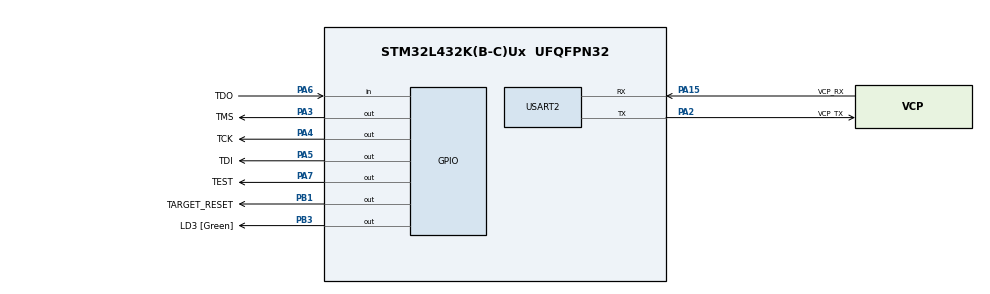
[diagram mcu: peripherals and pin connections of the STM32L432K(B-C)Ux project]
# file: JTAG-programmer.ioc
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Mcu.Family=STM32L4
Mcu.Name=STM32L432K(B-C)Ux
Mcu.Package=UFQFPN32
NVIC.PriorityGroup=NVIC_PRIORITYGROUP_4
PA0.GPIO_Label=MCO [High speed clock in]
PA0.Mode=HSE-External-Clock-Source-for-LittleOrca
PA0.Signal=RCC_CK_IN
PA13\ (JTMS-SWDIO).GPIO_Label=SWDIO
PA13\ (JTMS-SWDIO).Mode=Serial_Wire
PA13\ (JTMS-SWDIO).Signal=SYS_JTMS-SWDIO
PA14\ (JTCK-SWCLK).GPIO_Label=SWCLK
PA14\ (JTCK-SWCLK).Mode=Serial_Wire
PA14\ (JTCK-SWCLK).Signal=SYS_JTCK-SWCLK
PA15\ (JTDI).GPIO_Label=VCP_RX
PA15\ (JTDI).Mode=Asynchronous
PA15\ (JTDI).Signal=USART2_RX
PA2.GPIO_Label=VCP_TX
PA2.Mode=Asynchronous
PA2.Signal=USART2_TX
PA3.GPIO_Label=TMS
PA3.GPIO_Speed=GPIO_SPEED_FREQ_VERY_HIGH
PA3.Signal=GPIO_Output
PA4.GPIO_Label=TCK
PA4.GPIO_Speed=GPIO_SPEED_FREQ_VERY_HIGH
PA4.Signal=GPIO_Output
PA5.GPIO_Label=TDI
PA5.GPIO_Speed=GPIO_SPEED_FREQ_VERY_HIGH
PA5.Signal=GPIO_Output
PA6.GPIO_Label=TDO
PA6.Signal=GPIO_Input
PA7.GPIO_Label=TEST
PA7.GPIO_Speed=GPIO_SPEED_FREQ_VERY_HIGH
PA7.Signal=GPIO_Output
PB1.GPIO_Label=TARGET_RESET
PB1.GPIO_Speed=GPIO_SPEED_FREQ_VERY_HIGH
PB1.Signal=GPIO_Output
PB3\ (JTDO-TRACESWO).GPIO_Label=LD3 [Green]
PB3\ (JTDO-TRACESWO).Signal=GPIO_Output
PC14-OSC32_IN\ (PC14).Mode=LSE-External-Oscillator
PC14-OSC32_IN\ (PC14).Signal=RCC_OSC32_IN
PC15-OSC32_OUT\ (PC15).Mode=LSE-External-Oscillator
PC15-OSC32_OUT\ (PC15).Signal=RCC_OSC32_OUT
ProjectManager.HeapSize=0x200
ProjectManager.StackSize=0x400
ProjectManager.TargetToolchain=STM32CubeIDE
RCC.AHBFreq_Value=16000000
RCC.APB1Freq_Value=16000000
RCC.APB1TimFreq_Value=16000000
RCC.APB2Freq_Value=16000000
RCC.APB2TimFreq_Value=16000000
RCC.CortexFreq_Value=16000000
RCC.HCLKFreq_Value=16000000
RCC.HSE_VALUE=8000000
RCC.HSI16_VALUE=16000000
RCC.HSI48_VALUE=48000000
RCC.HSI_VALUE=16000000
RCC.MSI_VALUE=4000000
RCC.PLLMUL=RCC_PLLMUL_4
RCC.PLLN=16
RCC.SYSCLKFreq_VALUE=16000000
RCC.SYSCLKSource=RCC_SYSCLKSOURCE_HSI
RCC.VCOOutputFreq_Value=64000000
USART2.VirtualMode-Asynchronous=VM_ASYNC
board=NUCLEO-L432KC

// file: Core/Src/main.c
/* USER CODE BEGIN Header */
/**
 ******************************************************************************
 * @file           : main.c
 * @brief          : Main program body
 ******************************************************************************
 * @attention
 *
 * Copyright (c) 2023 STMicroelectronics.
 * All rights reserved.
 *
 * This software is licensed under terms that can be found in the LICENSE file
 * in the root directory of this software component.
 * If no LICENSE file comes with this software, it is provided AS-IS.
 *
 ******************************************************************************
 */

/* USER CODE END Header */
#include "main.h"

/* USER CODE BEGIN Includes */
#include "stdio.h" // for printf
#include "JTAGfunc430.h"
#include "LowLevelFunc430.h"
#include "Devices430.h"
#include <memory.h> // for memset
#include <string.h> // for strncmp

//mine
#include "jtag_programmer.h"
#include "stdlib.h" // for malloc
/* USER CODE END Includes */

UART_HandleTypeDef huart2;

/* USER CODE BEGIN PV */
#ifdef __GNUC__
#define PUTCHAR_PROTOTYPE int __io_putchar(int ch)
#define GETCHAR_PROTOTYPE int __io_getchar(void)
#else
#define PUTCHAR_PROTOTYPE int fputc(int ch, FILE *f)
#define GETCHAR_PROTOTYPE int fgetc(FILE *f)
#endif

PUTCHAR_PROTOTYPE
{
  HAL_UART_Transmit(&huart2, (uint8_t *)&ch, 1, HAL_MAX_DELAY);
  return ch;
}

GETCHAR_PROTOTYPE
{
  uint8_t ch = 0;

  /* Clear the Overrun flag just before receiving the first character */
  __HAL_UART_CLEAR_OREFLAG(&huart2);

  /* Wait for reception of a character on the USART RX line and echo this
   * character on console */
  HAL_UART_Receive(&huart2, (uint8_t *)&ch, 1, HAL_MAX_DELAY);
  HAL_UART_Transmit(&huart2, (uint8_t *)&ch, 1, HAL_MAX_DELAY);
  return ch;
}
/* USER CODE END PV */

void SystemClock_Config(void);
static void MX_GPIO_Init(void);
static void MX_USART2_UART_Init(void);
/* USER CODE BEGIN PFP */
static void GPIO_DeInit(void);
static void GPIO_ReInit(void);
/* USER CODE END PFP */

/* USER CODE BEGIN 0 */

// return minimum of a and b. if equal, return a.
int min(int a, int b) {
	return (b < a) ? b : a;
}

/* USER CODE END 0 */

int main(void)
{

  /* MCU Configuration--------------------------------------------------------*/

  /* Reset of all peripherals, Initializes the Flash interface and the Systick. */
  HAL_Init();

  /* Configure the system clock */
  SystemClock_Config();

  /* Initialize all configured peripherals */
  MX_GPIO_Init();
  MX_USART2_UART_Init();

  /* Infinite loop */
  /* USER CODE BEGIN WHILE */
  while (1) {
	  char buf[16] = {0};
	  uint16_t buflen = 0;

	  HAL_StatusTypeDef ret = HAL_UARTEx_ReceiveToIdle(&huart2, (uint8_t*)&buf[0], 16, &buflen, TIMEOUT);
	  if(ret == HAL_OK) {
		  if(strncmp(buf, "Wakeup!", min(buflen, 7)) == 0) {
			  __HAL_UART_FLUSH_DRREGISTER(&huart2);
			  GPIO_ReInit();
			  program_sequence();
			  GPIO_DeInit();
		  }
	  } else {
		  printf("-vret is %d and received %d bytes : %s\n", ret, buflen, buf);
	  }

	  HAL_GPIO_TogglePin(LD3_GPIO_Port, LD3_Pin);
    /* USER CODE END WHILE */

	}
}

void SystemClock_Config(void)
{
  RCC_OscInitTypeDef RCC_OscInitStruct = {0};
  RCC_ClkInitTypeDef RCC_ClkInitStruct = {0};

  /** Configure the main internal regulator output voltage
  */
  if (HAL_PWREx_ControlVoltageScaling(PWR_REGULATOR_VOLTAGE_SCALE1) != HAL_OK)
  {
    Error_Handler();
  }

  /** Initializes the RCC Oscillators according to the specified parameters
  * in the RCC_OscInitTypeDef structure.
  */
  RCC_OscInitStruct.OscillatorType = RCC_OSCILLATORTYPE_HSI;
  RCC_OscInitStruct.HSIState = RCC_HSI_ON;
  RCC_OscInitStruct.HSICalibrationValue = RCC_HSICALIBRATION_DEFAULT;
  RCC_OscInitStruct.PLL.PLLState = RCC_PLL_NONE;
  if (HAL_RCC_OscConfig(&RCC_OscInitStruct) != HAL_OK)
  {
    Error_Handler();
  }

  /** Initializes the CPU, AHB and APB buses clocks
  */
  RCC_ClkInitStruct.ClockType = RCC_CLOCKTYPE_HCLK|RCC_CLOCKTYPE_SYSCLK
                              |RCC_CLOCKTYPE_PCLK1|RCC_CLOCKTYPE_PCLK2;
  RCC_ClkInitStruct.SYSCLKSource = RCC_SYSCLKSOURCE_HSI;
  RCC_ClkInitStruct.AHBCLKDivider = RCC_SYSCLK_DIV2;
  RCC_ClkInitStruct.APB1CLKDivider = RCC_HCLK_DIV1;
  RCC_ClkInitStruct.APB2CLKDivider = RCC_HCLK_DIV1;

  if (HAL_RCC_ClockConfig(&RCC_ClkInitStruct, FLASH_LATENCY_0) != HAL_OK)
  {
    Error_Handler();
  }
}

static void MX_USART2_UART_Init(void)
{

  huart2.Instance = USART2;
  huart2.Init.BaudRate = 115200;
  huart2.Init.WordLength = UART_WORDLENGTH_8B;
  huart2.Init.StopBits = UART_STOPBITS_1;
  huart2.Init.Parity = UART_PARITY_NONE;
  huart2.Init.Mode = UART_MODE_TX_RX;
  huart2.Init.HwFlowCtl = UART_HWCONTROL_NONE;
  huart2.Init.OverSampling = UART_OVERSAMPLING_16;
  huart2.Init.OneBitSampling = UART_ONE_BIT_SAMPLE_DISABLE;
  huart2.AdvancedInit.AdvFeatureInit = UART_ADVFEATURE_RXOVERRUNDISABLE_INIT;
  huart2.AdvancedInit.OverrunDisable = UART_ADVFEATURE_OVERRUN_DISABLE;
  if (HAL_UART_Init(&huart2) != HAL_OK)
  {
    Error_Handler();
  }

}

static void MX_GPIO_Init(void)
{
  LL_GPIO_InitTypeDef GPIO_InitStruct = {0};

  /* GPIO Ports Clock Enable */
  LL_AHB2_GRP1_EnableClock(LL_AHB2_GRP1_PERIPH_GPIOC);
  LL_AHB2_GRP1_EnableClock(LL_AHB2_GRP1_PERIPH_GPIOA);
  LL_AHB2_GRP1_EnableClock(LL_AHB2_GRP1_PERIPH_GPIOB);
  LL_AHB2_GRP1_EnableClock(LL_AHB2_GRP1_PERIPH_GPIOH);

  /**/
  LL_GPIO_ResetOutputPin(GPIOA, TARGET_RESET_Pin|TMS_Pin|TCK_Pin|TDI_Pin
                          |TEST_Pin);

  /**/
  LL_GPIO_ResetOutputPin(LD3_GPIO_Port, LD3_Pin);

  /**/
  GPIO_InitStruct.Pin = TARGET_RESET_Pin|TMS_Pin|TCK_Pin|TDI_Pin
                          |TEST_Pin;
  GPIO_InitStruct.Mode = LL_GPIO_MODE_OUTPUT;
  GPIO_InitStruct.Speed = LL_GPIO_SPEED_FREQ_VERY_HIGH;
  GPIO_InitStruct.OutputType = LL_GPIO_OUTPUT_PUSHPULL;
  GPIO_InitStruct.Pull = LL_GPIO_PULL_NO;
  LL_GPIO_Init(GPIOA, &GPIO_InitStruct);

  /**/
  GPIO_InitStruct.Pin = TDO_Pin;
  GPIO_InitStruct.Mode = LL_GPIO_MODE_INPUT;
  GPIO_InitStruct.Pull = LL_GPIO_PULL_NO;
  LL_GPIO_Init(TDO_GPIO_Port, &GPIO_InitStruct);

  /**/
  GPIO_InitStruct.Pin = LL_GPIO_PIN_0|LL_GPIO_PIN_1|LL_GPIO_PIN_4|LL_GPIO_PIN_5
                          |LL_GPIO_PIN_6|LL_GPIO_PIN_7;
  GPIO_InitStruct.Mode = LL_GPIO_MODE_ANALOG;
  GPIO_InitStruct.Pull = LL_GPIO_PULL_NO;
  LL_GPIO_Init(GPIOB, &GPIO_InitStruct);

  /**/
  GPIO_InitStruct.Pin = LL_GPIO_PIN_8|LL_GPIO_PIN_9|LL_GPIO_PIN_10|LL_GPIO_PIN_11
                          |LL_GPIO_PIN_12;
  GPIO_InitStruct.Mode = LL_GPIO_MODE_ANALOG;
  GPIO_InitStruct.Pull = LL_GPIO_PULL_NO;
  LL_GPIO_Init(GPIOA, &GPIO_InitStruct);

  /**/
  GPIO_InitStruct.Pin = LD3_Pin;
  GPIO_InitStruct.Mode = LL_GPIO_MODE_OUTPUT;
  GPIO_InitStruct.Speed = LL_GPIO_SPEED_FREQ_LOW;
  GPIO_InitStruct.OutputType = LL_GPIO_OUTPUT_PUSHPULL;
  GPIO_InitStruct.Pull = LL_GPIO_PULL_NO;
  LL_GPIO_Init(LD3_GPIO_Port, &GPIO_InitStruct);

  /**/
  GPIO_InitStruct.Pin = LL_GPIO_PIN_3;
  GPIO_InitStruct.Mode = LL_GPIO_MODE_ANALOG;
  GPIO_InitStruct.Pull = LL_GPIO_PULL_NO;
  LL_GPIO_Init(GPIOH, &GPIO_InitStruct);

}

/* USER CODE BEGIN 4 */

// deinits all JTAG pins
static void GPIO_DeInit(void)
{
  LL_GPIO_InitTypeDef GPIO_InitStruct = {0};

  // dont deinit reset!
  GPIO_InitStruct.Pin = /*TARGET_RESET_Pin|*/TMS_Pin|TCK_Pin|TDI_Pin|TEST_Pin|TDO_Pin;
  GPIO_InitStruct.Mode = LL_GPIO_MODE_ANALOG;
  GPIO_InitStruct.Pull = LL_GPIO_PULL_NO;
  LL_GPIO_Init(GPIOA, &GPIO_InitStruct);
}

static void GPIO_ReInit(void)
{
  LL_GPIO_InitTypeDef GPIO_InitStruct = {0};

  GPIO_InitStruct.Pin = /*TARGET_RESET_Pin|*/TMS_Pin|TCK_Pin|TDI_Pin
                          |TEST_Pin;
  GPIO_InitStruct.Mode = LL_GPIO_MODE_OUTPUT;
  GPIO_InitStruct.Speed = LL_GPIO_SPEED_FREQ_VERY_HIGH;
  GPIO_InitStruct.OutputType = LL_GPIO_OUTPUT_PUSHPULL;
  GPIO_InitStruct.Pull = LL_GPIO_PULL_NO;
  LL_GPIO_Init(GPIOA, &GPIO_InitStruct);

  /**/
  GPIO_InitStruct.Pin = TDO_Pin;
  GPIO_InitStruct.Mode = LL_GPIO_MODE_INPUT;
  GPIO_InitStruct.Pull = LL_GPIO_PULL_NO;
  LL_GPIO_Init(TDO_GPIO_Port, &GPIO_InitStruct);
}

/* USER CODE END 4 */

void Error_Handler(void)
{
	__disable_irq();
	while (1) {
	}
}
